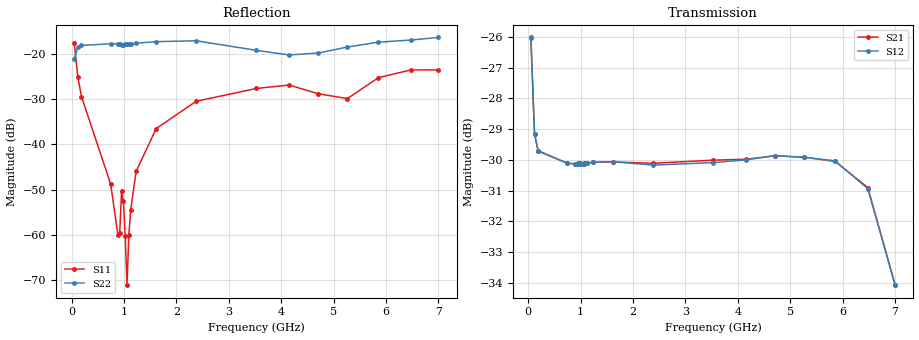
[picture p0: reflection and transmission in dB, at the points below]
! Integrated Device Technology
! Corporate Headquarters
! 6024 Silver Creek Valley Road
! San Jose, CA 95138  USA
! Phone:  1-408-284-8200
! Toll Free:  1-800-223-1366
! Webpage:  http://www.idt.com/
! Timing and RF Division
! 515 Groton Road, Suite 102
! Westford, MA 01886-6024
! Device:  F2258
! Description: Voltage Variable RF Attenuator
! Frequency:  50.0 -  6000.00 MHz
! Package:  3x3 mm Thin QFN Plastic Package: 16 pin
! Ports:  2 RF, 2 DC
!  Pin  1  = NC
!  Pin  2  = NC
!  Pin  3  = RF2  = Port 2
!  Pin  4  = GND
!  Pin  5  = Vdd
!  Pin  6  = NC
!  Pin  7  = VCTRL
!  Pin  8  = NC
!  Pin  9  = GND
!  Pin 10  = RF1  = Port 1
!  Pin 11  = NC
!  Pin 12  = NC
!  Pin 13  = NC
!  Pin 14  = NC
!  Pin 15  = NC
!  Pin 16  = NC
! Vcntrl:  1.670 Volts
! Vdd:  +3.300 Volts
! Current:  1.159 mA
! Data:  The device was measured on a the F2258 evaluation board which has
!  individual transmission lines to the RF pins.  Data was collected
!  using a calibrated network analyzer.  The evaluation board was
!  de-embedded using a TRL calibration technique.
!  The reference plane is the edge of the package pin.
! Misc:  SN 10
!  Action Tracker AT0285
! Date Measured:  2014-12-10
! Date:  2016-01-13  MJV
! Note:
!  Integrated Device Technology supplies this data as a sample of measured
!  data at the package pin for this product.  Your particular data for this
!  product may vary.
!  Data was taken at 25 degrees C.
!  Integrated Device Technology reserves the right to change this data at anytime.
!Freq_(GHz)  S11M_(dB)  S11P_(deg)  S21M_(dB)  S21P_(deg)  S12M_(dB)  S12P_(deg)  S22M_(dB)  S22P_(deg)
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# GHz S dB R 50
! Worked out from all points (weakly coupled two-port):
!   201 points, 50 MHz to 7 GHz, reference 50 ohm
!   highest |S21| = -26.01 dB at 50 MHz (marker M1); lowest = -34.1 dB at 7 GHz (marker M2)
!   lowest |S11| = -71.1 dB at 1.058 GHz (marker M3), VSWR 1.00, Z = 50 + j0.00865 ohm
!   |S11| at or under -10 dB: start of sweep to end of sweep
!   |S22| runs from -21.1 to -16.3 dB; largest |S21 - S12| = 0.00034
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0.05  -17.52 -110.0  -26.01 -50.6  -26.04 -50.6  -21.13 -42.9
0.1195  -25.11 -105.1  -29.15 -27.1  -29.15 -27.1  -18.57 -12.4
0.189  -29.46 -106.7  -29.70 -18.7  -29.72 -18.7  -18.14 -8.4
0.745  -48.73 -124.8  -30.11 -10.7  -30.11 -10.7  -17.75 -9.5
0.884  -60.00 169.0  -30.13 -11.0  -30.13 -11.0  -17.80 -11.4
0.91875  -59.49 130.4  -30.13 -11.1  -30.13 -11.1  -17.81 -11.9
0.9535  -50.39 -146.4  -30.11 -11.3  -30.14 -11.2  -18.01 -11.4
0.98825  -52.46 -159.8  -30.11 -11.4  -30.12 -11.4  -17.98 -12.2
1.023  -60.31 -166.6  -30.13 -11.5  -30.13 -11.5  -17.92 -12.6
1.05775  -71.09 18.1  -30.14 -11.6  -30.11 -11.7  -17.86 -12.8
1.0925  -60.10 40.4  -30.11 -11.8  -30.11 -11.8  -17.83 -13.2
1.12725  -54.54 44.4  -30.10 -12.0  -30.11 -12.0  -17.77 -13.7
1.2315  -45.96 30.3  -30.08 -12.6  -30.08 -12.6  -17.64 -14.7
1.61375  -36.51 28.0  -30.07 -15.6  -30.06 -15.6  -17.29 -18.7
2.37825  -30.46 45.3  -30.11 -21.6  -30.17 -21.6  -17.10 -25.5
3.525  -27.64 90.3  -30.01 -31.5  -30.09 -31.4  -19.21 -41.3
4.1505  -26.88 104.3  -29.98 -37.4  -30.00 -37.3  -20.23 -57.4
4.7065  -28.80 94.9  -29.87 -42.9  -29.86 -42.9  -19.81 -67.0
5.2625  -29.87 52.3  -29.91 -49.1  -29.92 -49.1  -18.48 -69.6
5.85325  -25.25 28.5  -30.05 -57.8  -30.03 -57.8  -17.41 -69.4
6.47875  -23.53 40.5  -30.90 -70.0  -30.94 -70.0  -16.93 -85.4
7  -23.54 83.8  -34.07 -71.3  -34.08 -71.2  -16.35 -128.3
